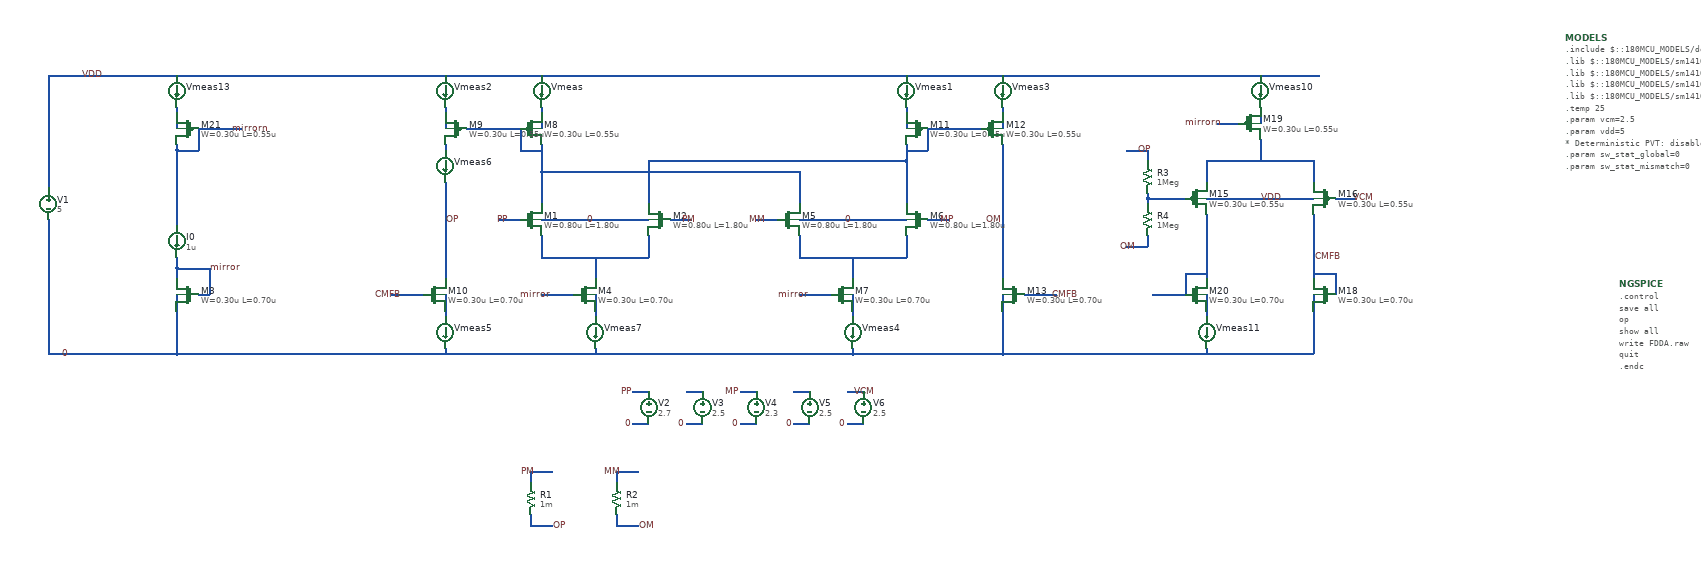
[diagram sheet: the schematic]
v {xschem version=3.4.7 file_version=1.2}
G {}
K {}
V {}
S {}
E {}
N -140 -220 -140 -180 {lab=#net1}
N -340 -180 -140 -180 {lab=#net1}
N -340 -220 -340 -180 {lab=#net1}
N -240 -180 -240 -140 {lab=#net1}
N -1020 0 -720 0 {lab=0}
N -1020 -80 -1020 0 {lab=0}
N -1020 -160 -1020 -140 {lab=mirror}
N -1020 -160 -960 -160 {lab=mirror}
N -960 -160 -960 -110 {lab=mirror}
N -1020 -180 -1020 -160 {lab=mirror}
N -1260 -250 -1260 0 {lab=0}
N -1260 0 -1020 0 {lab=0}
N -1260 -520 -1260 -310 {lab=VDD}
N -1260 -520 -1020 -520 {lab=VDD}
N -340 -250 -140 -250 {lab=0}
N 340 -220 340 -180 {lab=#net2}
N 140 -180 340 -180 {lab=#net2}
N 140 -220 140 -180 {lab=#net2}
N 140 -250 340 -250 {lab=0}
N -320 -0 140 -0 {lab=0}
N 140 0 240 0 {lab=0}
N -140 -360 -140 -280 {lab=#net3}
N -140 -360 340 -360 {lab=#net3}
N 340 -360 340 -280 {lab=#net3}
N 140 -340 140 -280 {lab=#net4}
N -340 -340 140 -340 {lab=#net4}
N -340 -340 -340 -280 {lab=#net4}
N -1010 -520 -740 -520 {lab=VDD}
N -340 -520 -140 -520 {lab=VDD}
N -170 70 -140 70 {lab=PP}
N -170 130 -140 130 {lab=0}
N -70 70 -40 70 {lab=#net5}
N -70 130 -40 130 {lab=0}
N 30 70 60 70 {lab=MP}
N 30 130 60 130 {lab=0}
N 130 70 160 70 {lab=#net6}
N 130 130 160 130 {lab=0}
N 60 -250 100 -250 {lab=MM}
N 380 -250 420 -250 {lab=MP}
N -100 -250 -60 -250 {lab=PM}
N -420 -250 -380 -250 {lab=PP}
N -1020 -520 -1010 -520 {lab=VDD}
N -240 -110 -240 -80 {lab=#net7}
N -1020 -110 -1020 -80 {lab=0}
N -980 -110 -960 -110 {lab=mirror}
N -340 -110 -280 -110 {lab=mirror}
N -740 -520 -340 -520 {lab=VDD}
N -720 -0 -320 0 {lab=0}
N -140 -520 340 -520 {lab=VDD}
N -340 -460 -340 -450 {lab=#net8}
N -340 -390 -340 -340 {lab=#net4}
N -380 -420 -380 -380 {lab=#net4}
N -380 -380 -340 -380 {lab=#net4}
N -480 -420 -380 -420 {lab=#net4}
N -520 -460 -520 -450 {lab=#net9}
N -520 -180 -520 -140 {lab=OP}
N -520 -110 -520 -80 {lab=#net10}
N -620 -110 -560 -110 {lab=CMFB}
N -520 -450 -520 -420 {lab=#net9}
N -340 -450 -340 -420 {lab=#net8}
N 340 -460 340 -450 {lab=#net11}
N 380 -420 380 -380 {lab=#net3}
N 340 -380 380 -380 {lab=#net3}
N 380 -420 480 -420 {lab=#net3}
N 520 -180 520 -140 {lab=OM}
N 520 -80 520 0 {lab=0}
N 520 -110 520 -80 {lab=0}
N 560 -110 620 -110 {lab=CMFB}
N 520 -450 520 -420 {lab=#net12}
N 340 -450 340 -420 {lab=#net11}
N 520 -390 520 -180 {lab=OM}
N 340 -390 340 -360 {lab=#net3}
N 340 -520 520 -520 {lab=VDD}
N 520 -460 520 -450 {lab=#net12}
N 240 -0 520 -0 {lab=0}
N -360 220 -360 240 {lab=PM}
N -360 220 -320 220 {lab=PM}
N -360 300 -360 320 {lab=OP}
N -360 320 -320 320 {lab=OP}
N -200 220 -200 240 {lab=MM}
N -200 220 -160 220 {lab=MM}
N -200 300 -200 320 {lab=OM}
N -200 320 -160 320 {lab=OM}
N -520 -80 -520 -70 {lab=#net10}
N -520 -10 -520 -0 {lab=0}
N -520 -390 -520 -380 {lab=#net13}
N -520 -320 -520 -180 {lab=OP}
N -240 -10 -240 -0 {lab=0}
N -240 -80 -240 -70 {lab=#net7}
N 230 70 260 70 {lab=VCM}
N 230 130 260 130 {lab=0}
N 520 0 1010 0 {lab=0}
N 820 -290 860 -290 {lab=#net14}
N 790 -300 790 -290 {lab=#net14}
N 790 -290 790 -280 {lab=#net14}
N 750 -200 790 -200 {lab=OM}
N 790 -220 790 -200 {lab=OM}
N 790 -380 790 -360 {lab=OP}
N 750 -380 790 -380 {lab=OP}
N 520 -520 1110 -520 {lab=VDD}
N -980 -420 -980 -380 {lab=mirrorn}
N -1020 -460 -1020 -450 {lab=#net15}
N -1020 -450 -1020 -420 {lab=#net15}
N -1020 -390 -1020 -380 {lab=mirrorn}
N -1020 -380 -980 -380 {lab=mirrorn}
N -1020 -380 -1020 -240 {lab=mirrorn}
N -980 -420 -900 -420 {lab=mirrorn}
N 920 -430 960 -430 {lab=mirrorn}
N 900 -360 900 -320 {lab=#net16}
N 900 -360 1100 -360 {lab=#net16}
N 1100 -360 1100 -320 {lab=#net16}
N 1000 -400 1000 -360 {lab=#net16}
N 1140 -290 1180 -290 {lab=VCM}
N 790 -290 820 -290 {lab=#net14}
N 900 -290 1100 -290 {lab=VDD}
N 1000 -460 1000 -430 {lab=#net17}
N 1100 -260 1100 -140 {lab=CMFB}
N 1100 -110 1100 -0 {lab=0}
N 1010 -0 1100 -0 {lab=0}
N 1100 -150 1140 -150 {lab=CMFB}
N 1140 -150 1140 -110 {lab=CMFB}
N 900 -260 900 -140 {lab=#net18}
N 860 -150 900 -150 {lab=#net18}
N 860 -150 860 -110 {lab=#net18}
N 900 -80 900 -70 {lab=#net19}
N 900 -10 900 -0 {lab=0}
N 800 -110 860 -110 {lab=#net18}
N 240 -180 240 -140 {lab=#net2}
N 240 -110 240 -80 {lab=#net20}
N 140 -110 200 -110 {lab=mirror}
N 240 -10 240 0 {lab=0}
N 240 -80 240 -70 {lab=#net20}
N 900 -110 900 -80 {lab=#net19}
C {symbols/nfet_06v0_nvt.sym} -360 -250 0 0 {name=M1
L=1.80u
W=0.80u
nf=1
m=1
ad="'int((nf+1)/2) * W/nf * 0.18u'"
pd="'2*int((nf+1)/2) * (W/nf + 0.18u)'"
as="'int((nf+2)/2) * W/nf * 0.18u'"
ps="'2*int((nf+2)/2) * (W/nf + 0.18u)'"
nrd="'0.18u / W'" nrs="'0.18u / W'"
sa=0 sb=0 sd=0
model=nfet_06v0
spiceprefix=X
}
C {symbols/nfet_06v0_nvt.sym} -120 -250 0 1 {name=M2
L=1.80u
W=0.80u
nf=1
m=1
ad="'int((nf+1)/2) * W/nf * 0.18u'"
pd="'2*int((nf+1)/2) * (W/nf + 0.18u)'"
as="'int((nf+2)/2) * W/nf * 0.18u'"
ps="'2*int((nf+2)/2) * (W/nf + 0.18u)'"
nrd="'0.18u / W'" nrs="'0.18u / W'"
sa=0 sb=0 sd=0
model=nfet_06v0
spiceprefix=X
}
C {symbols/nfet_06v0.sym} -1000 -110 0 1 {name=M3
L=0.70u
W=0.30u
nf=1
m=1
ad="'int((nf+1)/2) * W/nf * 0.18u'"
pd="'2*int((nf+1)/2) * (W/nf + 0.18u)'"
as="'int((nf+2)/2) * W/nf * 0.18u'"
ps="'2*int((nf+2)/2) * (W/nf + 0.18u)'"
nrd="'0.18u / W'" nrs="'0.18u / W'"
sa=0 sb=0 sd=0
model=nfet_06v0
spiceprefix=X
}
C {symbols/nfet_06v0.sym} -260 -110 0 0 {name=M4
L=0.70u
W=0.30u
nf=1
m=1
ad="'int((nf+1)/2) * W/nf * 0.18u'"
pd="'2*int((nf+1)/2) * (W/nf + 0.18u)'"
as="'int((nf+2)/2) * W/nf * 0.18u'"
ps="'2*int((nf+2)/2) * (W/nf + 0.18u)'"
nrd="'0.18u / W'" nrs="'0.18u / W'"
sa=0 sb=0 sd=0
model=nfet_06v0
spiceprefix=X
}
C {isource.sym} -1020 -210 0 0 {name=I0 value=1u}
C {vsource.sym} -1260 -280 0 0 {name=V1 value=5 savecurrent=false}
C {lab_wire.sym} -1220 0 0 0 {name=p3 sig_type=std_logic lab=0
}
C {lab_wire.sym} -240 -250 0 0 {name=p4 sig_type=std_logic lab=0
}
C {symbols/nfet_06v0_nvt.sym} 120 -250 0 0 {name=M5
L=1.80u
W=0.80u
nf=1
m=1
ad="'int((nf+1)/2) * W/nf * 0.18u'"
pd="'2*int((nf+1)/2) * (W/nf + 0.18u)'"
as="'int((nf+2)/2) * W/nf * 0.18u'"
ps="'2*int((nf+2)/2) * (W/nf + 0.18u)'"
nrd="'0.18u / W'" nrs="'0.18u / W'"
sa=0 sb=0 sd=0
model=nfet_06v0
spiceprefix=X
}
C {symbols/nfet_06v0_nvt.sym} 360 -250 0 1 {name=M6
L=1.80u
W=0.80u
nf=1
m=1
ad="'int((nf+1)/2) * W/nf * 0.18u'"
pd="'2*int((nf+1)/2) * (W/nf + 0.18u)'"
as="'int((nf+2)/2) * W/nf * 0.18u'"
ps="'2*int((nf+2)/2) * (W/nf + 0.18u)'"
nrd="'0.18u / W'" nrs="'0.18u / W'"
sa=0 sb=0 sd=0
model=nfet_06v0
spiceprefix=X
}
C {lab_wire.sym} 240 -250 0 0 {name=p7 sig_type=std_logic lab=0
}
C {lab_wire.sym} -320 -110 0 0 {name=p8 sig_type=std_logic lab=mirror
}
C {lab_wire.sym} -400 -250 0 0 {name=p1 sig_type=std_logic lab=PP
}
C {lab_wire.sym} -80 -250 0 1 {name=p2 sig_type=std_logic lab=PM
}
C {lab_wire.sym} 400 -250 0 1 {name=p5 sig_type=std_logic lab=MP
}
C {lab_wire.sym} 80 -250 0 0 {name=p6 sig_type=std_logic lab=MM
}
C {ammeter.sym} -340 -490 0 0 {name=Vmeas savecurrent=true spice_ignore=0}
C {ammeter.sym} 340 -490 0 0 {name=Vmeas1 savecurrent=true spice_ignore=0}
C {lab_wire.sym} -170 70 0 0 {name=p10 sig_type=std_logic lab=PP
}
C {vsource.sym} -140 100 0 0 {name=V2 value=2.7 savecurrent=false}
C {lab_wire.sym} -170 130 0 0 {name=p11 sig_type=std_logic lab=0
}
C {lab_wire.sym} -350 220 0 0 {name=p12 sig_type=std_logic lab=PM}
C {vsource.sym} -40 100 0 0 {name=V3 value=2.5 savecurrent=false}
C {lab_wire.sym} -70 130 0 0 {name=p13 sig_type=std_logic lab=0
}
C {lab_wire.sym} 30 70 0 0 {name=p14 sig_type=std_logic lab=MP
}
C {vsource.sym} 60 100 0 0 {name=V4 value=2.3 savecurrent=false}
C {lab_wire.sym} 30 130 0 0 {name=p15 sig_type=std_logic lab=0
}
C {lab_wire.sym} -190 220 0 0 {name=p16 sig_type=std_logic lab=MM
}
C {vsource.sym} 160 100 0 0 {name=V5 value=2.5 savecurrent=false}
C {lab_wire.sym} 130 130 0 0 {name=p17 sig_type=std_logic lab=0
}
C {code_shown.sym} 1670 -130 0 0 {name=NGSPICE only_toplevel=true
value="
.control
save all
op
show all
write FDDA.raw
quit
.endc
"}
C {code_shown.sym} 1570 -590 0 0 {name=MODELS only_toplevel=true
format="tcleval( @value )"
value="
.include $::180MCU_MODELS/design.ngspice

.lib $::180MCU_MODELS/sm141064.ngspice typical
.lib $::180MCU_MODELS/sm141064.ngspice res_typical
.lib $::180MCU_MODELS/sm141064.ngspice bjt_typical
.lib $::180MCU_MODELS/sm141064.ngspice mimcap_typical

.temp 25

.param vcm=2.5
.param vdd=5

* Deterministic PVT: disable random global/mismatch variation.
.param sw_stat_global=0
.param sw_stat_mismatch=0

"}
C {lab_wire.sym} -960 -160 0 1 {name=p18 sig_type=std_logic lab=mirror
}
C {symbols/pfet_06v0.sym} -360 -420 0 0 {name=M8
L=0.55u
W=0.30u
nf=1
m=1
ad="'int((nf+1)/2) * W/nf * 0.18u'"
pd="'2*int((nf+1)/2) * (W/nf + 0.18u)'"
as="'int((nf+2)/2) * W/nf * 0.18u'"
ps="'2*int((nf+2)/2) * (W/nf + 0.18u)'"
nrd="'0.18u / W'" nrs="'0.18u / W'"
sa=0 sb=0 sd=0
model=pfet_06v0
spiceprefix=X
}
C {symbols/pfet_06v0.sym} -500 -420 0 1 {name=M9
L=0.55u
W=0.30u
nf=1
m=1
ad="'int((nf+1)/2) * W/nf * 0.18u'"
pd="'2*int((nf+1)/2) * (W/nf + 0.18u)'"
as="'int((nf+2)/2) * W/nf * 0.18u'"
ps="'2*int((nf+2)/2) * (W/nf + 0.18u)'"
nrd="'0.18u / W'" nrs="'0.18u / W'"
sa=0 sb=0 sd=0
model=pfet_06v0
spiceprefix=X
}
C {ammeter.sym} -520 -490 0 0 {name=Vmeas2 savecurrent=true spice_ignore=0}
C {symbols/nfet_06v0.sym} -540 -110 0 0 {name=M10
L=0.70u
W=0.30u
nf=1
m=1
ad="'int((nf+1)/2) * W/nf * 0.18u'"
pd="'2*int((nf+1)/2) * (W/nf + 0.18u)'"
as="'int((nf+2)/2) * W/nf * 0.18u'"
ps="'2*int((nf+2)/2) * (W/nf + 0.18u)'"
nrd="'0.18u / W'" nrs="'0.18u / W'"
sa=0 sb=0 sd=0
model=nfet_06v0
spiceprefix=X
}
C {lab_wire.sym} -600 -110 0 0 {name=p19 sig_type=std_logic lab=CMFB
}
C {lab_wire.sym} -520 -250 0 1 {name=p20 sig_type=std_logic lab=OP
}
C {symbols/pfet_06v0.sym} 360 -420 0 1 {name=M11
L=0.55u
W=0.30u
nf=1
m=1
ad="'int((nf+1)/2) * W/nf * 0.18u'"
pd="'2*int((nf+1)/2) * (W/nf + 0.18u)'"
as="'int((nf+2)/2) * W/nf * 0.18u'"
ps="'2*int((nf+2)/2) * (W/nf + 0.18u)'"
nrd="'0.18u / W'" nrs="'0.18u / W'"
sa=0 sb=0 sd=0
model=pfet_06v0
spiceprefix=X
}
C {symbols/pfet_06v0.sym} 500 -420 0 0 {name=M12
L=0.55u
W=0.30u
nf=1
m=1
ad="'int((nf+1)/2) * W/nf * 0.18u'"
pd="'2*int((nf+1)/2) * (W/nf + 0.18u)'"
as="'int((nf+2)/2) * W/nf * 0.18u'"
ps="'2*int((nf+2)/2) * (W/nf + 0.18u)'"
nrd="'0.18u / W'" nrs="'0.18u / W'"
sa=0 sb=0 sd=0
model=pfet_06v0
spiceprefix=X
}
C {symbols/nfet_06v0.sym} 540 -110 0 1 {name=M13
L=0.70u
W=0.30u
nf=1
m=1
ad="'int((nf+1)/2) * W/nf * 0.18u'"
pd="'2*int((nf+1)/2) * (W/nf + 0.18u)'"
as="'int((nf+2)/2) * W/nf * 0.18u'"
ps="'2*int((nf+2)/2) * (W/nf + 0.18u)'"
nrd="'0.18u / W'" nrs="'0.18u / W'"
sa=0 sb=0 sd=0
model=nfet_06v0
spiceprefix=X
}
C {lab_wire.sym} 610 -110 0 1 {name=p21 sig_type=std_logic lab=CMFB
}
C {lab_wire.sym} 520 -250 0 0 {name=p22 sig_type=std_logic lab=OM
}
C {ammeter.sym} 520 -490 0 0 {name=Vmeas3 savecurrent=true spice_ignore=0}
C {res.sym} -360 270 0 0 {name=R1
value=1m
footprint=1206
device=resistor
m=1}
C {res.sym} -200 270 0 0 {name=R2
value=1m
footprint=1206
device=resistor
m=1}
C {lab_wire.sym} -320 320 0 1 {name=p23 sig_type=std_logic lab=OP
}
C {lab_wire.sym} -160 320 0 1 {name=p24 sig_type=std_logic lab=OM
}
C {ammeter.sym} -520 -40 0 0 {name=Vmeas5 savecurrent=true spice_ignore=0}
C {ammeter.sym} -520 -350 0 0 {name=Vmeas6 savecurrent=true spice_ignore=0}
C {ammeter.sym} -240 -40 0 0 {name=Vmeas7 savecurrent=true spice_ignore=0}
C {lab_wire.sym} 1170 -290 0 1 {name=p26 sig_type=std_logic lab=VCM
}
C {lab_wire.sym} 240 70 0 1 {name=p27 sig_type=std_logic lab=VCM
}
C {vsource.sym} 260 100 0 0 {name=V6 value=2.5 savecurrent=false}
C {ammeter.sym} 1000 -490 0 0 {name=Vmeas10 savecurrent=true spice_ignore=0}
C {res.sym} 790 -250 0 0 {name=R4
value=1Meg
footprint=1206
device=resistor
m=1}
C {res.sym} 790 -330 0 0 {name=R3
value=1Meg
footprint=1206
device=resistor
m=1}
C {lab_wire.sym} 770 -200 0 0 {name=p30 sig_type=std_logic lab=OM
}
C {lab_wire.sym} 770 -380 0 1 {name=p31 sig_type=std_logic lab=OP
}
C {symbols/pfet_06v0.sym} -1000 -420 0 1 {name=M21
L=0.55u
W=0.30u
nf=1
m=1
ad="'int((nf+1)/2) * W/nf * 0.18u'"
pd="'2*int((nf+1)/2) * (W/nf + 0.18u)'"
as="'int((nf+2)/2) * W/nf * 0.18u'"
ps="'2*int((nf+2)/2) * (W/nf + 0.18u)'"
nrd="'0.18u / W'" nrs="'0.18u / W'"
sa=0 sb=0 sd=0
model=pfet_06v0
spiceprefix=X
}
C {ammeter.sym} -1020 -490 0 0 {name=Vmeas13 savecurrent=true spice_ignore=0}
C {lab_wire.sym} -920 -420 0 1 {name=p32 sig_type=std_logic lab=mirrorn
}
C {symbols/pfet_06v0.sym} 980 -430 0 0 {name=M19
L=0.55u
W=0.30u
nf=1
m=1
ad="'int((nf+1)/2) * W/nf * 0.18u'"
pd="'2*int((nf+1)/2) * (W/nf + 0.18u)'"
as="'int((nf+2)/2) * W/nf * 0.18u'"
ps="'2*int((nf+2)/2) * (W/nf + 0.18u)'"
nrd="'0.18u / W'" nrs="'0.18u / W'"
sa=0 sb=0 sd=0
model=pfet_06v0
spiceprefix=X
}
C {lab_wire.sym} 930 -430 0 0 {name=p33 sig_type=std_logic lab=mirrorn
}
C {symbols/pfet_06v0.sym} 880 -290 0 0 {name=M15
L=0.55u
W=0.30u
nf=1
m=1
ad="'int((nf+1)/2) * W/nf * 0.18u'"
pd="'2*int((nf+1)/2) * (W/nf + 0.18u)'"
as="'int((nf+2)/2) * W/nf * 0.18u'"
ps="'2*int((nf+2)/2) * (W/nf + 0.18u)'"
nrd="'0.18u / W'" nrs="'0.18u / W'"
sa=0 sb=0 sd=0
model=pfet_06v0
spiceprefix=X
}
C {symbols/pfet_06v0.sym} 1120 -290 0 1 {name=M16
L=0.55u
W=0.30u
nf=1
m=1
ad="'int((nf+1)/2) * W/nf * 0.18u'"
pd="'2*int((nf+1)/2) * (W/nf + 0.18u)'"
as="'int((nf+2)/2) * W/nf * 0.18u'"
ps="'2*int((nf+2)/2) * (W/nf + 0.18u)'"
nrd="'0.18u / W'" nrs="'0.18u / W'"
sa=0 sb=0 sd=0
model=pfet_06v0
spiceprefix=X
}
C {lab_wire.sym} -1200 -520 0 1 {name=p29 sig_type=std_logic lab=VDD
}
C {lab_wire.sym} 1000 -290 0 1 {name=p34 sig_type=std_logic lab=VDD
}
C {symbols/nfet_06v0.sym} 1120 -110 0 1 {name=M18
L=0.70u
W=0.30u
nf=1
m=1
ad="'int((nf+1)/2) * W/nf * 0.18u'"
pd="'2*int((nf+1)/2) * (W/nf + 0.18u)'"
as="'int((nf+2)/2) * W/nf * 0.18u'"
ps="'2*int((nf+2)/2) * (W/nf + 0.18u)'"
nrd="'0.18u / W'" nrs="'0.18u / W'"
sa=0 sb=0 sd=0
model=nfet_06v0
spiceprefix=X
}
C {symbols/nfet_06v0.sym} 880 -110 0 0 {name=M20
L=0.70u
W=0.30u
nf=1
m=1
ad="'int((nf+1)/2) * W/nf * 0.18u'"
pd="'2*int((nf+1)/2) * (W/nf + 0.18u)'"
as="'int((nf+2)/2) * W/nf * 0.18u'"
ps="'2*int((nf+2)/2) * (W/nf + 0.18u)'"
nrd="'0.18u / W'" nrs="'0.18u / W'"
sa=0 sb=0 sd=0
model=nfet_06v0
spiceprefix=X
}
C {ammeter.sym} 900 -40 0 0 {name=Vmeas11 savecurrent=true spice_ignore=0}
C {lab_wire.sym} 1100 -180 0 1 {name=p35 sig_type=std_logic lab=CMFB
}
C {symbols/nfet_06v0.sym} 220 -110 0 0 {name=M7
L=0.70u
W=0.30u
nf=1
m=1
ad="'int((nf+1)/2) * W/nf * 0.18u'"
pd="'2*int((nf+1)/2) * (W/nf + 0.18u)'"
as="'int((nf+2)/2) * W/nf * 0.18u'"
ps="'2*int((nf+2)/2) * (W/nf + 0.18u)'"
nrd="'0.18u / W'" nrs="'0.18u / W'"
sa=0 sb=0 sd=0
model=nfet_06v0
spiceprefix=X
}
C {lab_wire.sym} 160 -110 0 0 {name=p9 sig_type=std_logic lab=mirror
}
C {ammeter.sym} 240 -40 0 0 {name=Vmeas4 savecurrent=true spice_ignore=0}
C {lab_wire.sym} 230 130 0 0 {name=p25 sig_type=std_logic lab=0
}
